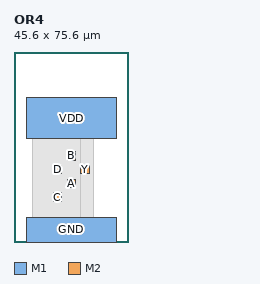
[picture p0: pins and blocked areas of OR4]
MACRO OR4
  CLASS CORE ;
  ORIGIN 0 0 ;
  SIZE 45.600 BY 75.600 ;
  SYMMETRY X Y ;
  SITE TR1um_access_site ;
  PIN VDD
    DIRECTION INOUT ;
    USE POWER ;
    PORT
      LAYER M1 ;
        RECT 5.000 41.000 40.600 57.600 ;
    END
  END VDD
  PIN GND
    DIRECTION INOUT ;
    USE GROUND ;
    PORT
      LAYER M1 ;
        RECT 5.000 0.000 40.600 9.800 ;
    END
  END GND
  PIN A
    DIRECTION INPUT ;
    USE SIGNAL ;
    PORT
      LAYER M2 ;
        RECT 21.100 21.600 24.500 25.000 ;
    END
  END A
  PIN B
    DIRECTION INPUT ;
    USE SIGNAL ;
    PORT
      LAYER M2 ;
        RECT 21.100 32.600 24.500 36.000 ;
    END
  END B
  PIN C
    DIRECTION INPUT ;
    USE SIGNAL ;
    PORT
      LAYER M2 ;
        RECT 15.600 16.100 19.000 19.500 ;
    END
  END C
  PIN D
    DIRECTION INPUT ;
    USE SIGNAL ;
    PORT
      LAYER M2 ;
        RECT 15.600 27.100 19.000 30.500 ;
    END
  END D
  PIN Y
    DIRECTION OUTPUT ;
    USE SIGNAL ;
    PORT
      LAYER M2 ;
        RECT 26.600 27.100 30.000 30.500 ;
    END
  END Y
  OBS
    LAYER M1 ;
      RECT 12.000 14.600 19.000 19.500 ;
    LAYER M1 ;
      RECT 21.100 21.600 27.600 25.000 ;
    LAYER M1 ;
      RECT 10.700 27.100 19.000 35.800 ;
    LAYER M1 ;
      RECT 18.100 32.600 24.500 36.000 ;
    LAYER M1 ;
      RECT 7.300 6.400 27.700 51.200 ;
    LAYER M1 ;
      RECT 13.100 41.000 15.700 51.200 ;
    LAYER M1 ;
      RECT 17.100 41.000 19.700 51.200 ;
    LAYER M1 ;
      RECT 21.100 41.000 23.700 51.200 ;
    LAYER M1 ;
      RECT 26.600 6.400 31.700 51.200 ;
    LAYER V1 ;
      RECT 16.600 17.100 18.000 18.500 ;
    LAYER V1 ;
      RECT 22.100 22.600 23.500 24.000 ;
    LAYER V1 ;
      RECT 16.600 28.100 18.000 29.500 ;
    LAYER V1 ;
      RECT 27.600 28.100 29.000 29.500 ;
    LAYER V1 ;
      RECT 22.100 33.600 23.500 35.000 ;
  END
END OR4
